VERSION 5.7 ;
  NOWIREEXTENSIONATPIN ON ;
  DIVIDERCHAR "/" ;
  BUSBITCHARS "[]" ;
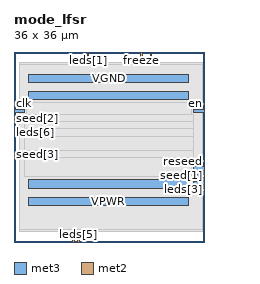
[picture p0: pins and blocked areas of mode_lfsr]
MACRO mode_lfsr
  CLASS BLOCK ;
  FOREIGN mode_lfsr ;
  ORIGIN 0.000 0.000 ;
  SIZE 36.000 BY 36.000 ;
  PIN VGND
    DIRECTION INOUT ;
    USE GROUND ;
    PORT
      LAYER met3 ;
        RECT 2.760 10.220 33.120 11.820 ;
    END
    PORT
      LAYER met3 ;
        RECT 2.760 30.220 33.120 31.820 ;
    END
  END VGND
  PIN VPWR
    DIRECTION INOUT ;
    USE POWER ;
    PORT
      LAYER met3 ;
        RECT 2.760 6.920 33.120 8.520 ;
    END
    PORT
      LAYER met3 ;
        RECT 2.760 26.920 33.120 28.520 ;
    END
  END VPWR
  PIN clk
    DIRECTION INPUT ;
    USE SIGNAL ;
    ANTENNAGATEAREA 0.852000 ;
    PORT
      LAYER met3 ;
        RECT 0.000 25.880 2.000 26.480 ;
    END
  END clk
  PIN en
    DIRECTION INPUT ;
    USE SIGNAL ;
    ANTENNAGATEAREA 0.213000 ;
    PORT
      LAYER met3 ;
        RECT 34.000 25.880 36.000 26.480 ;
    END
  END en
  PIN freeze
    DIRECTION INPUT ;
    USE SIGNAL ;
    ANTENNAGATEAREA 0.213000 ;
    PORT
      LAYER met2 ;
        RECT 24.010 34.000 24.290 36.000 ;
    END
  END freeze
  PIN leds[0]
    DIRECTION OUTPUT ;
    USE SIGNAL ;
    ANTENNAGATEAREA 0.990000 ;
    ANTENNADIFFAREA 0.445500 ;
    PORT
      LAYER met3 ;
        RECT 34.000 24.520 36.000 25.120 ;
    END
  END leds[0]
  PIN leds[1]
    DIRECTION OUTPUT ;
    USE SIGNAL ;
    ANTENNAGATEAREA 0.495000 ;
    ANTENNADIFFAREA 0.445500 ;
    PORT
      LAYER met2 ;
        RECT 13.890 34.000 14.170 36.000 ;
    END
  END leds[1]
  PIN leds[2]
    DIRECTION OUTPUT ;
    USE SIGNAL ;
    ANTENNAGATEAREA 0.742500 ;
    ANTENNADIFFAREA 0.445500 ;
    PORT
      LAYER met2 ;
        RECT 15.730 34.000 16.010 36.000 ;
    END
  END leds[2]
  PIN leds[3]
    DIRECTION OUTPUT ;
    USE SIGNAL ;
    ANTENNAGATEAREA 0.126000 ;
    ANTENNADIFFAREA 0.891000 ;
    PORT
      LAYER met3 ;
        RECT 34.000 9.560 36.000 10.160 ;
    END
  END leds[3]
  PIN leds[4]
    DIRECTION OUTPUT ;
    USE SIGNAL ;
    ANTENNADIFFAREA 0.891000 ;
    PORT
      LAYER met3 ;
        RECT 34.000 10.920 36.000 11.520 ;
    END
  END leds[4]
  PIN leds[5]
    DIRECTION OUTPUT ;
    USE SIGNAL ;
    ANTENNAGATEAREA 0.990000 ;
    ANTENNADIFFAREA 0.891000 ;
    PORT
      LAYER met2 ;
        RECT 12.050 0.000 12.330 2.000 ;
    END
  END leds[5]
  PIN leds[6]
    DIRECTION OUTPUT ;
    USE SIGNAL ;
    ANTENNAGATEAREA 0.373500 ;
    ANTENNADIFFAREA 0.445500 ;
    PORT
      LAYER met3 ;
        RECT 0.000 20.440 2.000 21.040 ;
    END
  END leds[6]
  PIN leds[7]
    DIRECTION OUTPUT ;
    USE SIGNAL ;
    ANTENNAGATEAREA 1.116000 ;
    ANTENNADIFFAREA 0.445500 ;
    PORT
      LAYER met2 ;
        RECT 11.130 0.000 11.410 2.000 ;
    END
  END leds[7]
  PIN reseed
    DIRECTION INPUT ;
    USE SIGNAL ;
    ANTENNAGATEAREA 0.213000 ;
    PORT
      LAYER met3 ;
        RECT 34.000 15.000 36.000 15.600 ;
    END
  END reseed
  PIN rst
    DIRECTION INPUT ;
    USE SIGNAL ;
    ANTENNAGATEAREA 0.196500 ;
    PORT
      LAYER met3 ;
        RECT 0.000 24.520 2.000 25.120 ;
    END
  END rst
  PIN seed[0]
    DIRECTION INPUT ;
    USE SIGNAL ;
    ANTENNAGATEAREA 0.213000 ;
    PORT
      LAYER met3 ;
        RECT 34.000 13.640 36.000 14.240 ;
    END
  END seed[0]
  PIN seed[1]
    DIRECTION INPUT ;
    USE SIGNAL ;
    ANTENNAGATEAREA 0.213000 ;
    PORT
      LAYER met3 ;
        RECT 34.000 12.280 36.000 12.880 ;
    END
  END seed[1]
  PIN seed[2]
    DIRECTION INPUT ;
    USE SIGNAL ;
    ANTENNAGATEAREA 0.213000 ;
    PORT
      LAYER met3 ;
        RECT 0.000 23.160 2.000 23.760 ;
    END
  END seed[2]
  PIN seed[3]
    DIRECTION INPUT ;
    USE SIGNAL ;
    ANTENNAGATEAREA 0.213000 ;
    PORT
      LAYER met3 ;
        RECT 0.000 16.360 2.000 16.960 ;
    END
  END seed[3]
  PIN tick
    DIRECTION INPUT ;
    USE SIGNAL ;
    ANTENNAGATEAREA 0.213000 ;
    PORT
      LAYER met2 ;
        RECT 25.850 34.000 26.130 36.000 ;
    END
  END tick
  OBS
      LAYER nwell ;
        RECT 2.570 2.635 33.310 32.830 ;
      LAYER li1 ;
        RECT 2.760 2.635 33.120 32.725 ;
      LAYER met1 ;
        RECT 0.990 2.480 35.810 33.280 ;
      LAYER met2 ;
        RECT 1.020 33.720 13.610 34.000 ;
        RECT 14.450 33.720 15.450 34.000 ;
        RECT 16.290 33.720 23.730 34.000 ;
        RECT 24.570 33.720 25.570 34.000 ;
        RECT 26.410 33.720 35.790 34.000 ;
        RECT 1.020 2.280 35.790 33.720 ;
        RECT 1.020 2.000 10.850 2.280 ;
        RECT 11.690 2.000 11.770 2.280 ;
        RECT 12.610 2.000 35.790 2.280 ;
      LAYER met3 ;
        RECT 2.400 24.120 33.600 26.345 ;
        RECT 2.400 22.760 34.000 24.120 ;
        RECT 2.000 21.440 34.000 22.760 ;
        RECT 2.400 20.040 34.000 21.440 ;
        RECT 2.000 17.360 34.000 20.040 ;
        RECT 2.400 16.000 34.000 17.360 ;
        RECT 2.400 15.960 33.600 16.000 ;
        RECT 2.000 12.415 33.600 15.960 ;
  END
END mode_lfsr
END LIBRARY

